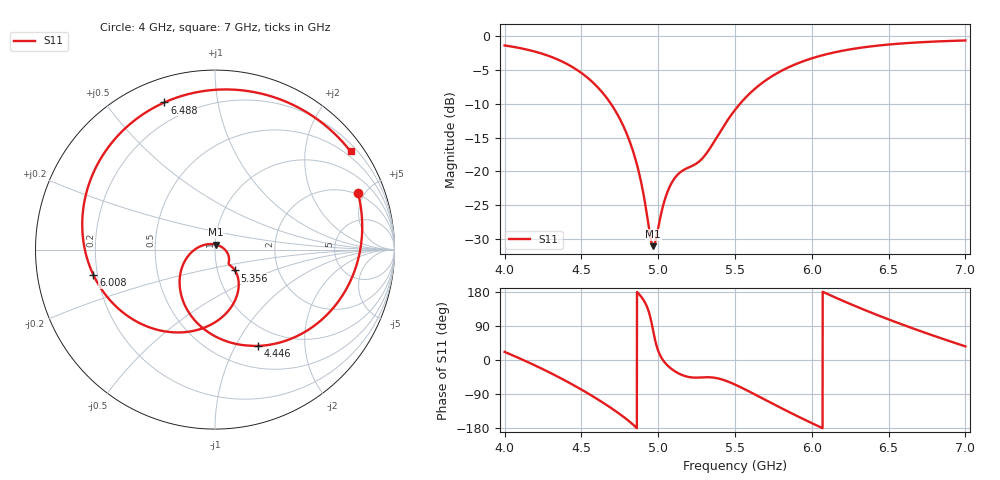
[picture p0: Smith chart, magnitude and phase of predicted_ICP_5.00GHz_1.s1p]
! ICP-predicted S11, target max centred GHz at -10 dB. Complex ensemble mean (passive and causal);
! its |S11| can differ slightly from the dB-domain mean reported in designs.csv.
!  Air_gap = 3.24mm
!  W_Patch = 14.95mm
!  L_Patch = 19.51mm
!  Sx = 0.96mm
!  Sy = 3.81mm
!  W_Patch1 = 13.47mm
!  WS = 1.05mm
!  Curve_Amp1 = 0.9mm
!  Extra = 4.47mm
# GHz S MA R 50
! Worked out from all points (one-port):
!   3001 points, 4 GHz to 7 GHz, reference 50 ohm
!   lowest |S11| = -31.1 dB at 4.968 GHz (marker M1), VSWR 1.06, Z = 50.6 + j2.75 ohm
!   |S11| at or under -10 dB: 4.693 GHz to 5.532 GHz (839.2 MHz wide, 16.4 % of centre)
!   S11 on the Smith chart (normalised r, x): 4 GHz: 1.92, +4.50; 4.446 GHz: 0.76, -1.24; 5.356 GHz: 1.21, -0.29; 6.008 GHz: 0.18, -0.10; 6.488 GHz: 0.11, +0.71; 7 GHz: 0.36, +3.05
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4  0.8565 21.4
4.093  0.8216 5.1
4.182  0.7795 -11.3
4.375  0.6508 -50.1
4.446  0.5886 -65.7
4.526  0.509 -84.1
4.614  0.4108 -105.8
4.75  0.2453 -142.7
4.86  0.1142 -179.6
4.901  0.07107 160.3
4.95  0.03238 110.5
4.968  0.02801 75.6
5.053  0.06703 -11.2
5.125  0.09435 -33.8
5.27  0.1195 -46.3
5.356  0.1605 -46.3
5.5  0.2854 -64.8
5.597  0.3788 -84.1
5.706  0.4774 -107.0
5.875  0.6086 -142.0
6.008  0.6919 -168.1
6.128  0.7524 169.5
6.25  0.8012 147.9
6.374  0.8397 127.1
6.488  0.8671 109.0
6.625  0.8922 88.2
6.798  0.9148 63.4
7  0.9323 35.9
